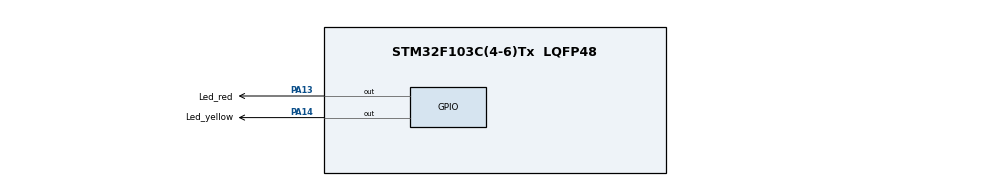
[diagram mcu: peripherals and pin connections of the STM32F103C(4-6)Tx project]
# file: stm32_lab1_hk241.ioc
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Mcu.Family=STM32F1
Mcu.Name=STM32F103C(4-6)Tx
Mcu.Package=LQFP48
NVIC.PriorityGroup=NVIC_PRIORITYGROUP_4
PA13.GPIO_Label=Led_red
PA13.Signal=GPIO_Output
PA14.GPIO_Label=Led_yellow
PA14.Signal=GPIO_Output
ProjectManager.HeapSize=0x200
ProjectManager.StackSize=0x400
ProjectManager.TargetToolchain=STM32CubeIDE
RCC.APB1Freq_Value=8000000
RCC.APB2Freq_Value=8000000
board=custom

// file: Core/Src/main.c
/* USER CODE BEGIN Header */
/**
  ******************************************************************************
  * @file           : main.c
  * @brief          : Main program body
  ******************************************************************************
  * @attention
  *
  * Copyright (c) 2024 STMicroelectronics.
  * All rights reserved.
  *
  * This software is licensed under terms that can be found in the LICENSE file
  * in the root directory of this software component.
  * If no LICENSE file comes with this software, it is provided AS-IS.
  *
  ******************************************************************************
  */
/* USER CODE END Header */
#include "main.h"

/* USER CODE BEGIN Includes */
#include "ex1.h"
/* USER CODE END Includes */

void SystemClock_Config(void);
static void MX_GPIO_Init(void);

int main(void)
{

  /* MCU Configuration--------------------------------------------------------*/

  /* Reset of all peripherals, Initializes the Flash interface and the Systick. */
  HAL_Init();

  /* Configure the system clock */
  SystemClock_Config();

  /* Initialize all configured peripherals */
  MX_GPIO_Init();

  /* Infinite loop */
  /* USER CODE BEGIN WHILE */
  int i = 0;
  while (1)
  {
    /* USER CODE END WHILE */

    /* USER CODE BEGIN 3 */
	 if(i==0){
setAllClock();
HAL_Delay(2000);

clearAllClock();
HAL_Delay(2000);

setNumberOnClock(6);
HAL_Delay(2000);

clearNumberOnClock(6);
HAL_Delay(2000);
 i = 1;
	 }
runClock();
HAL_Delay(100);
  }
  /* USER CODE END 3 */
}

void SystemClock_Config(void)
{
  RCC_OscInitTypeDef RCC_OscInitStruct = {0};
  RCC_ClkInitTypeDef RCC_ClkInitStruct = {0};

  /** Initializes the RCC Oscillators according to the specified parameters
  * in the RCC_OscInitTypeDef structure.
  */
  RCC_OscInitStruct.OscillatorType = RCC_OSCILLATORTYPE_HSI;
  RCC_OscInitStruct.HSIState = RCC_HSI_ON;
  RCC_OscInitStruct.HSICalibrationValue = RCC_HSICALIBRATION_DEFAULT;
  RCC_OscInitStruct.PLL.PLLState = RCC_PLL_NONE;
  if (HAL_RCC_OscConfig(&RCC_OscInitStruct) != HAL_OK)
  {
    Error_Handler();
  }

  /** Initializes the CPU, AHB and APB buses clocks
  */
  RCC_ClkInitStruct.ClockType = RCC_CLOCKTYPE_HCLK|RCC_CLOCKTYPE_SYSCLK
                              |RCC_CLOCKTYPE_PCLK1|RCC_CLOCKTYPE_PCLK2;
  RCC_ClkInitStruct.SYSCLKSource = RCC_SYSCLKSOURCE_HSI;
  RCC_ClkInitStruct.AHBCLKDivider = RCC_SYSCLK_DIV1;
  RCC_ClkInitStruct.APB1CLKDivider = RCC_HCLK_DIV1;
  RCC_ClkInitStruct.APB2CLKDivider = RCC_HCLK_DIV1;

  if (HAL_RCC_ClockConfig(&RCC_ClkInitStruct, FLASH_LATENCY_0) != HAL_OK)
  {
    Error_Handler();
  }
}

static void MX_GPIO_Init(void)
{
  GPIO_InitTypeDef GPIO_InitStruct = {0};

  /* GPIO Ports Clock Enable */
  __HAL_RCC_GPIOA_CLK_ENABLE();
  __HAL_RCC_GPIOB_CLK_ENABLE();

  /*Configure GPIO pin Output Level */
  HAL_GPIO_WritePin(GPIOA, o5_Pin|o10_Pin|o15_Pin|o20_Pin
                          |o25_Pin|o30_Pin|red_Pin|yellow_Pin
                          |green_Pin|red1_Pin|yellow1_Pin|green1_Pin, GPIO_PIN_RESET);

  /*Configure GPIO pin Output Level */
  HAL_GPIO_WritePin(GPIOB, seg1_Pin|seg2_Pin|seg3_Pin|o50_Pin
                          |o55_Pin|o60_Pin|seg4_Pin|seg5_Pin
                          |seg6_Pin|seg7_Pin|o35_Pin|o40_Pin
                          |o45_Pin, GPIO_PIN_RESET);

  /*Configure GPIO pins : o5_Pin o10_Pin o15_Pin o20_Pin
                           o25_Pin o30_Pin red_Pin yellow_Pin
                           green_Pin red1_Pin yellow1_Pin green1_Pin */
  GPIO_InitStruct.Pin = o5_Pin|o10_Pin|o15_Pin|o20_Pin
                          |o25_Pin|o30_Pin|red_Pin|yellow_Pin
                          |green_Pin|red1_Pin|yellow1_Pin|green1_Pin;
  GPIO_InitStruct.Mode = GPIO_MODE_OUTPUT_PP;
  GPIO_InitStruct.Pull = GPIO_NOPULL;
  GPIO_InitStruct.Speed = GPIO_SPEED_FREQ_LOW;
  HAL_GPIO_Init(GPIOA, &GPIO_InitStruct);

  /*Configure GPIO pins : seg1_Pin seg2_Pin seg3_Pin o50_Pin
                           o55_Pin o60_Pin seg4_Pin seg5_Pin
                           seg6_Pin seg7_Pin o35_Pin o40_Pin
                           o45_Pin */
  GPIO_InitStruct.Pin = seg1_Pin|seg2_Pin|seg3_Pin|o50_Pin
                          |o55_Pin|o60_Pin|seg4_Pin|seg5_Pin
                          |seg6_Pin|seg7_Pin|o35_Pin|o40_Pin
                          |o45_Pin;
  GPIO_InitStruct.Mode = GPIO_MODE_OUTPUT_PP;
  GPIO_InitStruct.Pull = GPIO_NOPULL;
  GPIO_InitStruct.Speed = GPIO_SPEED_FREQ_LOW;
  HAL_GPIO_Init(GPIOB, &GPIO_InitStruct);

}

void Error_Handler(void)
{
  __disable_irq();
  while (1)
  {
  }
}
